VERSION 5.7 ;
  NOWIREEXTENSIONATPIN ON ;
  DIVIDERCHAR "/" ;
  BUSBITCHARS "[]" ;
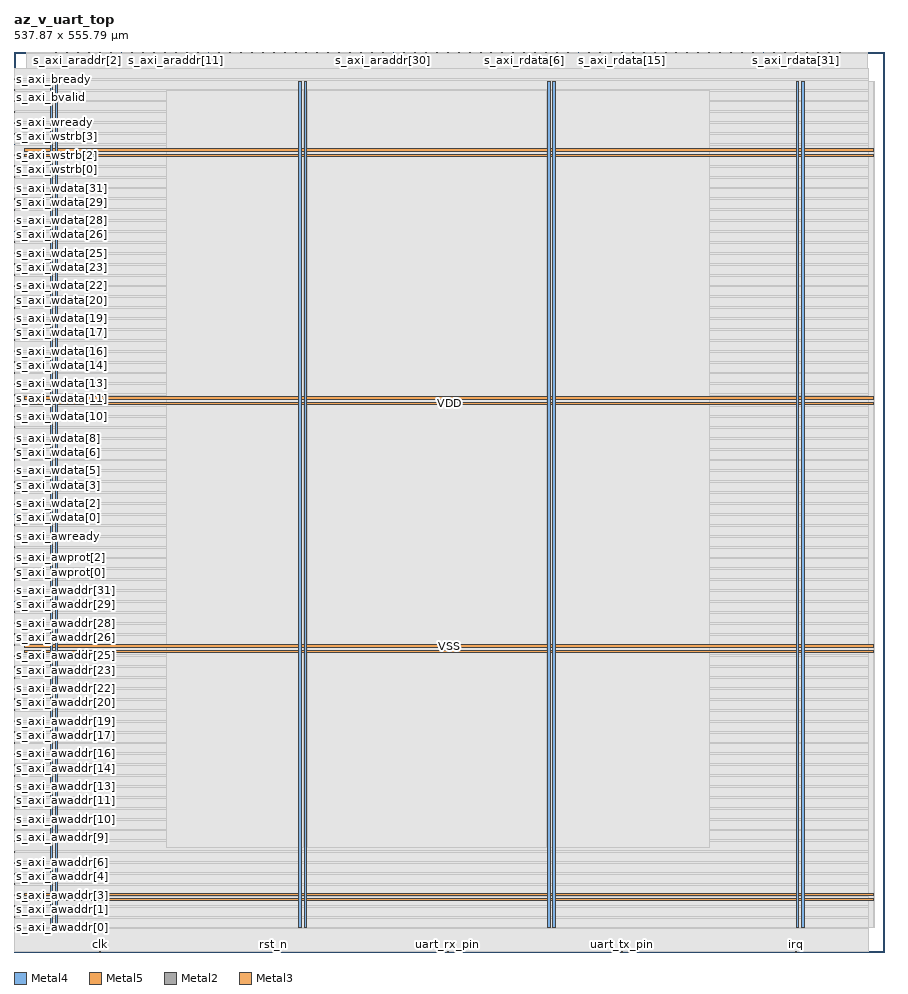
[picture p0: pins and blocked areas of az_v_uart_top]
MACRO az_v_uart_top
  CLASS BLOCK ;
  FOREIGN az_v_uart_top ;
  ORIGIN 0.000 0.000 ;
  SIZE 537.870 BY 555.790 ;
  PIN VDD
    DIRECTION INOUT ;
    USE POWER ;
    PORT
      LAYER Metal4 ;
        RECT 22.240 15.380 23.840 537.340 ;
    END
    PORT
      LAYER Metal4 ;
        RECT 175.840 15.380 177.440 537.340 ;
    END
    PORT
      LAYER Metal4 ;
        RECT 329.440 15.380 331.040 537.340 ;
    END
    PORT
      LAYER Metal4 ;
        RECT 483.040 15.380 484.640 537.340 ;
    END
    PORT
      LAYER Metal5 ;
        RECT 6.720 31.530 530.880 33.130 ;
    END
    PORT
      LAYER Metal5 ;
        RECT 6.720 184.710 530.880 186.310 ;
    END
    PORT
      LAYER Metal5 ;
        RECT 6.720 337.890 530.880 339.490 ;
    END
    PORT
      LAYER Metal5 ;
        RECT 6.720 491.070 530.880 492.670 ;
    END
  END VDD
  PIN VSS
    DIRECTION INOUT ;
    USE GROUND ;
    PORT
      LAYER Metal4 ;
        RECT 25.540 15.380 27.140 537.340 ;
    END
    PORT
      LAYER Metal4 ;
        RECT 179.140 15.380 180.740 537.340 ;
    END
    PORT
      LAYER Metal4 ;
        RECT 332.740 15.380 334.340 537.340 ;
    END
    PORT
      LAYER Metal4 ;
        RECT 486.340 15.380 487.940 537.340 ;
    END
    PORT
      LAYER Metal5 ;
        RECT 6.720 34.830 530.880 36.430 ;
    END
    PORT
      LAYER Metal5 ;
        RECT 6.720 188.010 530.880 189.610 ;
    END
    PORT
      LAYER Metal5 ;
        RECT 6.720 341.190 530.880 342.790 ;
    END
    PORT
      LAYER Metal5 ;
        RECT 6.720 494.370 530.880 495.970 ;
    END
  END VSS
  PIN clk
    DIRECTION INPUT ;
    USE SIGNAL ;
    ANTENNAGATEAREA 4.738000 ;
    PORT
      LAYER Metal2 ;
        RECT 52.640 0.000 53.200 0.560 ;
    END
  END clk
  PIN irq
    DIRECTION OUTPUT ;
    USE SIGNAL ;
    ANTENNADIFFAREA 0.897600 ;
    PORT
      LAYER Metal2 ;
        RECT 482.720 0.000 483.280 0.560 ;
    END
  END irq
  PIN rst_n
    DIRECTION INPUT ;
    USE SIGNAL ;
    ANTENNAGATEAREA 0.396000 ;
    PORT
      LAYER Metal2 ;
        RECT 160.160 0.000 160.720 0.560 ;
    END
  END rst_n
  PIN s_axi_araddr[0]
    DIRECTION INPUT ;
    USE SIGNAL ;
    ANTENNAGATEAREA 0.396000 ;
    PORT
      LAYER Metal2 ;
        RECT 25.760 555.230 26.320 555.790 ;
    END
  END s_axi_araddr[0]
  PIN s_axi_araddr[10]
    DIRECTION INPUT ;
    USE SIGNAL ;
    PORT
      LAYER Metal2 ;
        RECT 92.960 555.230 93.520 555.790 ;
    END
  END s_axi_araddr[10]
  PIN s_axi_araddr[11]
    DIRECTION INPUT ;
    USE SIGNAL ;
    PORT
      LAYER Metal2 ;
        RECT 99.680 555.230 100.240 555.790 ;
    END
  END s_axi_araddr[11]
  PIN s_axi_araddr[12]
    DIRECTION INPUT ;
    USE SIGNAL ;
    PORT
      LAYER Metal2 ;
        RECT 106.400 555.230 106.960 555.790 ;
    END
  END s_axi_araddr[12]
  PIN s_axi_araddr[13]
    DIRECTION INPUT ;
    USE SIGNAL ;
    PORT
      LAYER Metal2 ;
        RECT 113.120 555.230 113.680 555.790 ;
    END
  END s_axi_araddr[13]
  PIN s_axi_araddr[14]
    DIRECTION INPUT ;
    USE SIGNAL ;
    PORT
      LAYER Metal2 ;
        RECT 119.840 555.230 120.400 555.790 ;
    END
  END s_axi_araddr[14]
  PIN s_axi_araddr[15]
    DIRECTION INPUT ;
    USE SIGNAL ;
    PORT
      LAYER Metal2 ;
        RECT 126.560 555.230 127.120 555.790 ;
    END
  END s_axi_araddr[15]
  PIN s_axi_araddr[16]
    DIRECTION INPUT ;
    USE SIGNAL ;
    PORT
      LAYER Metal2 ;
        RECT 133.280 555.230 133.840 555.790 ;
    END
  END s_axi_araddr[16]
  PIN s_axi_araddr[17]
    DIRECTION INPUT ;
    USE SIGNAL ;
    PORT
      LAYER Metal2 ;
        RECT 140.000 555.230 140.560 555.790 ;
    END
  END s_axi_araddr[17]
  PIN s_axi_araddr[18]
    DIRECTION INPUT ;
    USE SIGNAL ;
    PORT
      LAYER Metal2 ;
        RECT 146.720 555.230 147.280 555.790 ;
    END
  END s_axi_araddr[18]
  PIN s_axi_araddr[19]
    DIRECTION INPUT ;
    USE SIGNAL ;
    PORT
      LAYER Metal2 ;
        RECT 153.440 555.230 154.000 555.790 ;
    END
  END s_axi_araddr[19]
  PIN s_axi_araddr[1]
    DIRECTION INPUT ;
    USE SIGNAL ;
    ANTENNAGATEAREA 0.396000 ;
    PORT
      LAYER Metal2 ;
        RECT 32.480 555.230 33.040 555.790 ;
    END
  END s_axi_araddr[1]
  PIN s_axi_araddr[20]
    DIRECTION INPUT ;
    USE SIGNAL ;
    PORT
      LAYER Metal2 ;
        RECT 160.160 555.230 160.720 555.790 ;
    END
  END s_axi_araddr[20]
  PIN s_axi_araddr[21]
    DIRECTION INPUT ;
    USE SIGNAL ;
    PORT
      LAYER Metal2 ;
        RECT 166.880 555.230 167.440 555.790 ;
    END
  END s_axi_araddr[21]
  PIN s_axi_araddr[22]
    DIRECTION INPUT ;
    USE SIGNAL ;
    PORT
      LAYER Metal2 ;
        RECT 173.600 555.230 174.160 555.790 ;
    END
  END s_axi_araddr[22]
  PIN s_axi_araddr[23]
    DIRECTION INPUT ;
    USE SIGNAL ;
    PORT
      LAYER Metal2 ;
        RECT 180.320 555.230 180.880 555.790 ;
    END
  END s_axi_araddr[23]
  PIN s_axi_araddr[24]
    DIRECTION INPUT ;
    USE SIGNAL ;
    PORT
      LAYER Metal2 ;
        RECT 187.040 555.230 187.600 555.790 ;
    END
  END s_axi_araddr[24]
  PIN s_axi_araddr[25]
    DIRECTION INPUT ;
    USE SIGNAL ;
    PORT
      LAYER Metal2 ;
        RECT 193.760 555.230 194.320 555.790 ;
    END
  END s_axi_araddr[25]
  PIN s_axi_araddr[26]
    DIRECTION INPUT ;
    USE SIGNAL ;
    PORT
      LAYER Metal2 ;
        RECT 200.480 555.230 201.040 555.790 ;
    END
  END s_axi_araddr[26]
  PIN s_axi_araddr[27]
    DIRECTION INPUT ;
    USE SIGNAL ;
    PORT
      LAYER Metal2 ;
        RECT 207.200 555.230 207.760 555.790 ;
    END
  END s_axi_araddr[27]
  PIN s_axi_araddr[28]
    DIRECTION INPUT ;
    USE SIGNAL ;
    PORT
      LAYER Metal2 ;
        RECT 213.920 555.230 214.480 555.790 ;
    END
  END s_axi_araddr[28]
  PIN s_axi_araddr[29]
    DIRECTION INPUT ;
    USE SIGNAL ;
    PORT
      LAYER Metal2 ;
        RECT 220.640 555.230 221.200 555.790 ;
    END
  END s_axi_araddr[29]
  PIN s_axi_araddr[2]
    DIRECTION INPUT ;
    USE SIGNAL ;
    ANTENNAGATEAREA 0.396000 ;
    PORT
      LAYER Metal2 ;
        RECT 39.200 555.230 39.760 555.790 ;
    END
  END s_axi_araddr[2]
  PIN s_axi_araddr[30]
    DIRECTION INPUT ;
    USE SIGNAL ;
    PORT
      LAYER Metal2 ;
        RECT 227.360 555.230 227.920 555.790 ;
    END
  END s_axi_araddr[30]
  PIN s_axi_araddr[31]
    DIRECTION INPUT ;
    USE SIGNAL ;
    PORT
      LAYER Metal2 ;
        RECT 234.080 555.230 234.640 555.790 ;
    END
  END s_axi_araddr[31]
  PIN s_axi_araddr[3]
    DIRECTION INPUT ;
    USE SIGNAL ;
    ANTENNAGATEAREA 0.396000 ;
    PORT
      LAYER Metal2 ;
        RECT 45.920 555.230 46.480 555.790 ;
    END
  END s_axi_araddr[3]
  PIN s_axi_araddr[4]
    DIRECTION INPUT ;
    USE SIGNAL ;
    ANTENNAGATEAREA 0.396000 ;
    PORT
      LAYER Metal2 ;
        RECT 52.640 555.230 53.200 555.790 ;
    END
  END s_axi_araddr[4]
  PIN s_axi_araddr[5]
    DIRECTION INPUT ;
    USE SIGNAL ;
    ANTENNAGATEAREA 0.396000 ;
    PORT
      LAYER Metal2 ;
        RECT 59.360 555.230 59.920 555.790 ;
    END
  END s_axi_araddr[5]
  PIN s_axi_araddr[6]
    DIRECTION INPUT ;
    USE SIGNAL ;
    PORT
      LAYER Metal2 ;
        RECT 66.080 555.230 66.640 555.790 ;
    END
  END s_axi_araddr[6]
  PIN s_axi_araddr[7]
    DIRECTION INPUT ;
    USE SIGNAL ;
    PORT
      LAYER Metal2 ;
        RECT 72.800 555.230 73.360 555.790 ;
    END
  END s_axi_araddr[7]
  PIN s_axi_araddr[8]
    DIRECTION INPUT ;
    USE SIGNAL ;
    PORT
      LAYER Metal2 ;
        RECT 79.520 555.230 80.080 555.790 ;
    END
  END s_axi_araddr[8]
  PIN s_axi_araddr[9]
    DIRECTION INPUT ;
    USE SIGNAL ;
    PORT
      LAYER Metal2 ;
        RECT 86.240 555.230 86.800 555.790 ;
    END
  END s_axi_araddr[9]
  PIN s_axi_arprot[0]
    DIRECTION INPUT ;
    USE SIGNAL ;
    PORT
      LAYER Metal2 ;
        RECT 240.800 555.230 241.360 555.790 ;
    END
  END s_axi_arprot[0]
  PIN s_axi_arprot[1]
    DIRECTION INPUT ;
    USE SIGNAL ;
    PORT
      LAYER Metal2 ;
        RECT 247.520 555.230 248.080 555.790 ;
    END
  END s_axi_arprot[1]
  PIN s_axi_arprot[2]
    DIRECTION INPUT ;
    USE SIGNAL ;
    PORT
      LAYER Metal2 ;
        RECT 254.240 555.230 254.800 555.790 ;
    END
  END s_axi_arprot[2]
  PIN s_axi_arready
    DIRECTION OUTPUT ;
    USE SIGNAL ;
    ANTENNADIFFAREA 0.897600 ;
    PORT
      LAYER Metal2 ;
        RECT 267.680 555.230 268.240 555.790 ;
    END
  END s_axi_arready
  PIN s_axi_arvalid
    DIRECTION INPUT ;
    USE SIGNAL ;
    ANTENNAGATEAREA 0.396000 ;
    PORT
      LAYER Metal2 ;
        RECT 260.960 555.230 261.520 555.790 ;
    END
  END s_axi_arvalid
  PIN s_axi_awaddr[0]
    DIRECTION INPUT ;
    USE SIGNAL ;
    ANTENNAGATEAREA 0.396000 ;
    PORT
      LAYER Metal3 ;
        RECT 0.000 14.560 0.560 15.120 ;
    END
  END s_axi_awaddr[0]
  PIN s_axi_awaddr[10]
    DIRECTION INPUT ;
    USE SIGNAL ;
    PORT
      LAYER Metal3 ;
        RECT 0.000 81.760 0.560 82.320 ;
    END
  END s_axi_awaddr[10]
  PIN s_axi_awaddr[11]
    DIRECTION INPUT ;
    USE SIGNAL ;
    PORT
      LAYER Metal3 ;
        RECT 0.000 88.480 0.560 89.040 ;
    END
  END s_axi_awaddr[11]
  PIN s_axi_awaddr[12]
    DIRECTION INPUT ;
    USE SIGNAL ;
    PORT
      LAYER Metal3 ;
        RECT 0.000 95.200 0.560 95.760 ;
    END
  END s_axi_awaddr[12]
  PIN s_axi_awaddr[13]
    DIRECTION INPUT ;
    USE SIGNAL ;
    PORT
      LAYER Metal3 ;
        RECT 0.000 101.920 0.560 102.480 ;
    END
  END s_axi_awaddr[13]
  PIN s_axi_awaddr[14]
    DIRECTION INPUT ;
    USE SIGNAL ;
    PORT
      LAYER Metal3 ;
        RECT 0.000 108.640 0.560 109.200 ;
    END
  END s_axi_awaddr[14]
  PIN s_axi_awaddr[15]
    DIRECTION INPUT ;
    USE SIGNAL ;
    PORT
      LAYER Metal3 ;
        RECT 0.000 115.360 0.560 115.920 ;
    END
  END s_axi_awaddr[15]
  PIN s_axi_awaddr[16]
    DIRECTION INPUT ;
    USE SIGNAL ;
    PORT
      LAYER Metal3 ;
        RECT 0.000 122.080 0.560 122.640 ;
    END
  END s_axi_awaddr[16]
  PIN s_axi_awaddr[17]
    DIRECTION INPUT ;
    USE SIGNAL ;
    PORT
      LAYER Metal3 ;
        RECT 0.000 128.800 0.560 129.360 ;
    END
  END s_axi_awaddr[17]
  PIN s_axi_awaddr[18]
    DIRECTION INPUT ;
    USE SIGNAL ;
    PORT
      LAYER Metal3 ;
        RECT 0.000 135.520 0.560 136.080 ;
    END
  END s_axi_awaddr[18]
  PIN s_axi_awaddr[19]
    DIRECTION INPUT ;
    USE SIGNAL ;
    PORT
      LAYER Metal3 ;
        RECT 0.000 142.240 0.560 142.800 ;
    END
  END s_axi_awaddr[19]
  PIN s_axi_awaddr[1]
    DIRECTION INPUT ;
    USE SIGNAL ;
    ANTENNAGATEAREA 0.396000 ;
    PORT
      LAYER Metal3 ;
        RECT 0.000 21.280 0.560 21.840 ;
    END
  END s_axi_awaddr[1]
  PIN s_axi_awaddr[20]
    DIRECTION INPUT ;
    USE SIGNAL ;
    PORT
      LAYER Metal3 ;
        RECT 0.000 148.960 0.560 149.520 ;
    END
  END s_axi_awaddr[20]
  PIN s_axi_awaddr[21]
    DIRECTION INPUT ;
    USE SIGNAL ;
    PORT
      LAYER Metal3 ;
        RECT 0.000 155.680 0.560 156.240 ;
    END
  END s_axi_awaddr[21]
  PIN s_axi_awaddr[22]
    DIRECTION INPUT ;
    USE SIGNAL ;
    PORT
      LAYER Metal3 ;
        RECT 0.000 162.400 0.560 162.960 ;
    END
  END s_axi_awaddr[22]
  PIN s_axi_awaddr[23]
    DIRECTION INPUT ;
    USE SIGNAL ;
    PORT
      LAYER Metal3 ;
        RECT 0.000 169.120 0.560 169.680 ;
    END
  END s_axi_awaddr[23]
  PIN s_axi_awaddr[24]
    DIRECTION INPUT ;
    USE SIGNAL ;
    PORT
      LAYER Metal3 ;
        RECT 0.000 175.840 0.560 176.400 ;
    END
  END s_axi_awaddr[24]
  PIN s_axi_awaddr[25]
    DIRECTION INPUT ;
    USE SIGNAL ;
    PORT
      LAYER Metal3 ;
        RECT 0.000 182.560 0.560 183.120 ;
    END
  END s_axi_awaddr[25]
  PIN s_axi_awaddr[26]
    DIRECTION INPUT ;
    USE SIGNAL ;
    PORT
      LAYER Metal3 ;
        RECT 0.000 189.280 0.560 189.840 ;
    END
  END s_axi_awaddr[26]
  PIN s_axi_awaddr[27]
    DIRECTION INPUT ;
    USE SIGNAL ;
    PORT
      LAYER Metal3 ;
        RECT 0.000 196.000 0.560 196.560 ;
    END
  END s_axi_awaddr[27]
  PIN s_axi_awaddr[28]
    DIRECTION INPUT ;
    USE SIGNAL ;
    PORT
      LAYER Metal3 ;
        RECT 0.000 202.720 0.560 203.280 ;
    END
  END s_axi_awaddr[28]
  PIN s_axi_awaddr[29]
    DIRECTION INPUT ;
    USE SIGNAL ;
    PORT
      LAYER Metal3 ;
        RECT 0.000 209.440 0.560 210.000 ;
    END
  END s_axi_awaddr[29]
  PIN s_axi_awaddr[2]
    DIRECTION INPUT ;
    USE SIGNAL ;
    ANTENNAGATEAREA 0.396000 ;
    PORT
      LAYER Metal3 ;
        RECT 0.000 28.000 0.560 28.560 ;
    END
  END s_axi_awaddr[2]
  PIN s_axi_awaddr[30]
    DIRECTION INPUT ;
    USE SIGNAL ;
    PORT
      LAYER Metal3 ;
        RECT 0.000 216.160 0.560 216.720 ;
    END
  END s_axi_awaddr[30]
  PIN s_axi_awaddr[31]
    DIRECTION INPUT ;
    USE SIGNAL ;
    PORT
      LAYER Metal3 ;
        RECT 0.000 222.880 0.560 223.440 ;
    END
  END s_axi_awaddr[31]
  PIN s_axi_awaddr[3]
    DIRECTION INPUT ;
    USE SIGNAL ;
    ANTENNAGATEAREA 0.396000 ;
    PORT
      LAYER Metal3 ;
        RECT 0.000 34.720 0.560 35.280 ;
    END
  END s_axi_awaddr[3]
  PIN s_axi_awaddr[4]
    DIRECTION INPUT ;
    USE SIGNAL ;
    ANTENNAGATEAREA 0.396000 ;
    PORT
      LAYER Metal3 ;
        RECT 0.000 41.440 0.560 42.000 ;
    END
  END s_axi_awaddr[4]
  PIN s_axi_awaddr[5]
    DIRECTION INPUT ;
    USE SIGNAL ;
    ANTENNAGATEAREA 0.396000 ;
    PORT
      LAYER Metal3 ;
        RECT 0.000 48.160 0.560 48.720 ;
    END
  END s_axi_awaddr[5]
  PIN s_axi_awaddr[6]
    DIRECTION INPUT ;
    USE SIGNAL ;
    PORT
      LAYER Metal3 ;
        RECT 0.000 54.880 0.560 55.440 ;
    END
  END s_axi_awaddr[6]
  PIN s_axi_awaddr[7]
    DIRECTION INPUT ;
    USE SIGNAL ;
    PORT
      LAYER Metal3 ;
        RECT 0.000 61.600 0.560 62.160 ;
    END
  END s_axi_awaddr[7]
  PIN s_axi_awaddr[8]
    DIRECTION INPUT ;
    USE SIGNAL ;
    PORT
      LAYER Metal3 ;
        RECT 0.000 68.320 0.560 68.880 ;
    END
  END s_axi_awaddr[8]
  PIN s_axi_awaddr[9]
    DIRECTION INPUT ;
    USE SIGNAL ;
    PORT
      LAYER Metal3 ;
        RECT 0.000 75.040 0.560 75.600 ;
    END
  END s_axi_awaddr[9]
  PIN s_axi_awprot[0]
    DIRECTION INPUT ;
    USE SIGNAL ;
    PORT
      LAYER Metal3 ;
        RECT 0.000 229.600 0.560 230.160 ;
    END
  END s_axi_awprot[0]
  PIN s_axi_awprot[1]
    DIRECTION INPUT ;
    USE SIGNAL ;
    PORT
      LAYER Metal3 ;
        RECT 0.000 236.320 0.560 236.880 ;
    END
  END s_axi_awprot[1]
  PIN s_axi_awprot[2]
    DIRECTION INPUT ;
    USE SIGNAL ;
    PORT
      LAYER Metal3 ;
        RECT 0.000 243.040 0.560 243.600 ;
    END
  END s_axi_awprot[2]
  PIN s_axi_awready
    DIRECTION OUTPUT ;
    USE SIGNAL ;
    ANTENNADIFFAREA 0.897600 ;
    PORT
      LAYER Metal3 ;
        RECT 0.000 256.480 0.560 257.040 ;
    END
  END s_axi_awready
  PIN s_axi_awvalid
    DIRECTION INPUT ;
    USE SIGNAL ;
    ANTENNAGATEAREA 0.396000 ;
    PORT
      LAYER Metal3 ;
        RECT 0.000 249.760 0.560 250.320 ;
    END
  END s_axi_awvalid
  PIN s_axi_bready
    DIRECTION INPUT ;
    USE SIGNAL ;
    ANTENNAGATEAREA 0.396000 ;
    PORT
      LAYER Metal3 ;
        RECT 0.000 538.720 0.560 539.280 ;
    END
  END s_axi_bready
  PIN s_axi_bresp[0]
    DIRECTION OUTPUT ;
    USE SIGNAL ;
    ANTENNADIFFAREA 0.360800 ;
    PORT
      LAYER Metal3 ;
        RECT 0.000 518.560 0.560 519.120 ;
    END
  END s_axi_bresp[0]
  PIN s_axi_bresp[1]
    DIRECTION OUTPUT ;
    USE SIGNAL ;
    ANTENNADIFFAREA 0.360800 ;
    PORT
      LAYER Metal3 ;
        RECT 0.000 525.280 0.560 525.840 ;
    END
  END s_axi_bresp[1]
  PIN s_axi_bvalid
    DIRECTION OUTPUT ;
    USE SIGNAL ;
    ANTENNADIFFAREA 0.897600 ;
    PORT
      LAYER Metal3 ;
        RECT 0.000 532.000 0.560 532.560 ;
    END
  END s_axi_bvalid
  PIN s_axi_rdata[0]
    DIRECTION OUTPUT ;
    USE SIGNAL ;
    ANTENNADIFFAREA 0.897600 ;
    PORT
      LAYER Metal2 ;
        RECT 274.400 555.230 274.960 555.790 ;
    END
  END s_axi_rdata[0]
  PIN s_axi_rdata[10]
    DIRECTION OUTPUT ;
    USE SIGNAL ;
    ANTENNADIFFAREA 0.897600 ;
    PORT
      LAYER Metal2 ;
        RECT 341.600 555.230 342.160 555.790 ;
    END
  END s_axi_rdata[10]
  PIN s_axi_rdata[11]
    DIRECTION OUTPUT ;
    USE SIGNAL ;
    ANTENNADIFFAREA 0.897600 ;
    PORT
      LAYER Metal2 ;
        RECT 348.320 555.230 348.880 555.790 ;
    END
  END s_axi_rdata[11]
  PIN s_axi_rdata[12]
    DIRECTION OUTPUT ;
    USE SIGNAL ;
    ANTENNADIFFAREA 0.897600 ;
    PORT
      LAYER Metal2 ;
        RECT 355.040 555.230 355.600 555.790 ;
    END
  END s_axi_rdata[12]
  PIN s_axi_rdata[13]
    DIRECTION OUTPUT ;
    USE SIGNAL ;
    ANTENNADIFFAREA 0.897600 ;
    PORT
      LAYER Metal2 ;
        RECT 361.760 555.230 362.320 555.790 ;
    END
  END s_axi_rdata[13]
  PIN s_axi_rdata[14]
    DIRECTION OUTPUT ;
    USE SIGNAL ;
    ANTENNADIFFAREA 0.897600 ;
    PORT
      LAYER Metal2 ;
        RECT 368.480 555.230 369.040 555.790 ;
    END
  END s_axi_rdata[14]
  PIN s_axi_rdata[15]
    DIRECTION OUTPUT ;
    USE SIGNAL ;
    ANTENNADIFFAREA 0.897600 ;
    PORT
      LAYER Metal2 ;
        RECT 375.200 555.230 375.760 555.790 ;
    END
  END s_axi_rdata[15]
  PIN s_axi_rdata[16]
    DIRECTION OUTPUT ;
    USE SIGNAL ;
    ANTENNADIFFAREA 0.897600 ;
    PORT
      LAYER Metal2 ;
        RECT 381.920 555.230 382.480 555.790 ;
    END
  END s_axi_rdata[16]
  PIN s_axi_rdata[17]
    DIRECTION OUTPUT ;
    USE SIGNAL ;
    ANTENNADIFFAREA 0.897600 ;
    PORT
      LAYER Metal2 ;
        RECT 388.640 555.230 389.200 555.790 ;
    END
  END s_axi_rdata[17]
  PIN s_axi_rdata[18]
    DIRECTION OUTPUT ;
    USE SIGNAL ;
    ANTENNADIFFAREA 0.897600 ;
    PORT
      LAYER Metal2 ;
        RECT 395.360 555.230 395.920 555.790 ;
    END
  END s_axi_rdata[18]
  PIN s_axi_rdata[19]
    DIRECTION OUTPUT ;
    USE SIGNAL ;
    ANTENNADIFFAREA 0.897600 ;
    PORT
      LAYER Metal2 ;
        RECT 402.080 555.230 402.640 555.790 ;
    END
  END s_axi_rdata[19]
  PIN s_axi_rdata[1]
    DIRECTION OUTPUT ;
    USE SIGNAL ;
    ANTENNADIFFAREA 0.897600 ;
    PORT
      LAYER Metal2 ;
        RECT 281.120 555.230 281.680 555.790 ;
    END
  END s_axi_rdata[1]
  PIN s_axi_rdata[20]
    DIRECTION OUTPUT ;
    USE SIGNAL ;
    ANTENNADIFFAREA 0.897600 ;
    PORT
      LAYER Metal2 ;
        RECT 408.800 555.230 409.360 555.790 ;
    END
  END s_axi_rdata[20]
  PIN s_axi_rdata[21]
    DIRECTION OUTPUT ;
    USE SIGNAL ;
    ANTENNADIFFAREA 0.897600 ;
    PORT
      LAYER Metal2 ;
        RECT 415.520 555.230 416.080 555.790 ;
    END
  END s_axi_rdata[21]
  PIN s_axi_rdata[22]
    DIRECTION OUTPUT ;
    USE SIGNAL ;
    ANTENNADIFFAREA 0.897600 ;
    PORT
      LAYER Metal2 ;
        RECT 422.240 555.230 422.800 555.790 ;
    END
  END s_axi_rdata[22]
  PIN s_axi_rdata[23]
    DIRECTION OUTPUT ;
    USE SIGNAL ;
    ANTENNADIFFAREA 0.897600 ;
    PORT
      LAYER Metal2 ;
        RECT 428.960 555.230 429.520 555.790 ;
    END
  END s_axi_rdata[23]
  PIN s_axi_rdata[24]
    DIRECTION OUTPUT ;
    USE SIGNAL ;
    ANTENNADIFFAREA 0.897600 ;
    PORT
      LAYER Metal2 ;
        RECT 435.680 555.230 436.240 555.790 ;
    END
  END s_axi_rdata[24]
  PIN s_axi_rdata[25]
    DIRECTION OUTPUT ;
    USE SIGNAL ;
    ANTENNADIFFAREA 0.897600 ;
    PORT
      LAYER Metal2 ;
        RECT 442.400 555.230 442.960 555.790 ;
    END
  END s_axi_rdata[25]
  PIN s_axi_rdata[26]
    DIRECTION OUTPUT ;
    USE SIGNAL ;
    ANTENNADIFFAREA 0.897600 ;
    PORT
      LAYER Metal2 ;
        RECT 449.120 555.230 449.680 555.790 ;
    END
  END s_axi_rdata[26]
  PIN s_axi_rdata[27]
    DIRECTION OUTPUT ;
    USE SIGNAL ;
    ANTENNADIFFAREA 0.897600 ;
    PORT
      LAYER Metal2 ;
        RECT 455.840 555.230 456.400 555.790 ;
    END
  END s_axi_rdata[27]
  PIN s_axi_rdata[28]
    DIRECTION OUTPUT ;
    USE SIGNAL ;
    ANTENNADIFFAREA 0.897600 ;
    PORT
      LAYER Metal2 ;
        RECT 462.560 555.230 463.120 555.790 ;
    END
  END s_axi_rdata[28]
  PIN s_axi_rdata[29]
    DIRECTION OUTPUT ;
    USE SIGNAL ;
    ANTENNADIFFAREA 0.897600 ;
    PORT
      LAYER Metal2 ;
        RECT 469.280 555.230 469.840 555.790 ;
    END
  END s_axi_rdata[29]
  PIN s_axi_rdata[2]
    DIRECTION OUTPUT ;
    USE SIGNAL ;
    ANTENNADIFFAREA 0.897600 ;
    PORT
      LAYER Metal2 ;
        RECT 287.840 555.230 288.400 555.790 ;
    END
  END s_axi_rdata[2]
  PIN s_axi_rdata[30]
    DIRECTION OUTPUT ;
    USE SIGNAL ;
    ANTENNADIFFAREA 0.897600 ;
    PORT
      LAYER Metal2 ;
        RECT 476.000 555.230 476.560 555.790 ;
    END
  END s_axi_rdata[30]
  PIN s_axi_rdata[31]
    DIRECTION OUTPUT ;
    USE SIGNAL ;
    ANTENNADIFFAREA 0.897600 ;
    PORT
      LAYER Metal2 ;
        RECT 482.720 555.230 483.280 555.790 ;
    END
  END s_axi_rdata[31]
  PIN s_axi_rdata[3]
    DIRECTION OUTPUT ;
    USE SIGNAL ;
    ANTENNADIFFAREA 0.897600 ;
    PORT
      LAYER Metal2 ;
        RECT 294.560 555.230 295.120 555.790 ;
    END
  END s_axi_rdata[3]
  PIN s_axi_rdata[4]
    DIRECTION OUTPUT ;
    USE SIGNAL ;
    ANTENNADIFFAREA 0.897600 ;
    PORT
      LAYER Metal2 ;
        RECT 301.280 555.230 301.840 555.790 ;
    END
  END s_axi_rdata[4]
  PIN s_axi_rdata[5]
    DIRECTION OUTPUT ;
    USE SIGNAL ;
    ANTENNADIFFAREA 0.897600 ;
    PORT
      LAYER Metal2 ;
        RECT 308.000 555.230 308.560 555.790 ;
    END
  END s_axi_rdata[5]
  PIN s_axi_rdata[6]
    DIRECTION OUTPUT ;
    USE SIGNAL ;
    ANTENNADIFFAREA 0.897600 ;
    PORT
      LAYER Metal2 ;
        RECT 314.720 555.230 315.280 555.790 ;
    END
  END s_axi_rdata[6]
  PIN s_axi_rdata[7]
    DIRECTION OUTPUT ;
    USE SIGNAL ;
    ANTENNADIFFAREA 0.897600 ;
    PORT
      LAYER Metal2 ;
        RECT 321.440 555.230 322.000 555.790 ;
    END
  END s_axi_rdata[7]
  PIN s_axi_rdata[8]
    DIRECTION OUTPUT ;
    USE SIGNAL ;
    ANTENNADIFFAREA 0.897600 ;
    PORT
      LAYER Metal2 ;
        RECT 328.160 555.230 328.720 555.790 ;
    END
  END s_axi_rdata[8]
  PIN s_axi_rdata[9]
    DIRECTION OUTPUT ;
    USE SIGNAL ;
    ANTENNADIFFAREA 0.897600 ;
    PORT
      LAYER Metal2 ;
        RECT 334.880 555.230 335.440 555.790 ;
    END
  END s_axi_rdata[9]
  PIN s_axi_rready
    DIRECTION INPUT ;
    USE SIGNAL ;
    ANTENNAGATEAREA 0.396000 ;
    PORT
      LAYER Metal2 ;
        RECT 509.600 555.230 510.160 555.790 ;
    END
  END s_axi_rready
  PIN s_axi_rresp[0]
    DIRECTION OUTPUT ;
    USE SIGNAL ;
    ANTENNADIFFAREA 0.360800 ;
    PORT
      LAYER Metal2 ;
        RECT 489.440 555.230 490.000 555.790 ;
    END
  END s_axi_rresp[0]
  PIN s_axi_rresp[1]
    DIRECTION OUTPUT ;
    USE SIGNAL ;
    ANTENNADIFFAREA 0.360800 ;
    PORT
      LAYER Metal2 ;
        RECT 496.160 555.230 496.720 555.790 ;
    END
  END s_axi_rresp[1]
  PIN s_axi_rvalid
    DIRECTION OUTPUT ;
    USE SIGNAL ;
    ANTENNADIFFAREA 0.897600 ;
    PORT
      LAYER Metal2 ;
        RECT 502.880 555.230 503.440 555.790 ;
    END
  END s_axi_rvalid
  PIN s_axi_wdata[0]
    DIRECTION INPUT ;
    USE SIGNAL ;
    ANTENNAGATEAREA 0.396000 ;
    PORT
      LAYER Metal3 ;
        RECT 0.000 263.200 0.560 263.760 ;
    END
  END s_axi_wdata[0]
  PIN s_axi_wdata[10]
    DIRECTION INPUT ;
    USE SIGNAL ;
    ANTENNAGATEAREA 0.396000 ;
    PORT
      LAYER Metal3 ;
        RECT 0.000 330.400 0.560 330.960 ;
    END
  END s_axi_wdata[10]
  PIN s_axi_wdata[11]
    DIRECTION INPUT ;
    USE SIGNAL ;
    ANTENNAGATEAREA 0.396000 ;
    PORT
      LAYER Metal3 ;
        RECT 0.000 337.120 0.560 337.680 ;
    END
  END s_axi_wdata[11]
  PIN s_axi_wdata[12]
    DIRECTION INPUT ;
    USE SIGNAL ;
    ANTENNAGATEAREA 0.396000 ;
    PORT
      LAYER Metal3 ;
        RECT 0.000 343.840 0.560 344.400 ;
    END
  END s_axi_wdata[12]
  PIN s_axi_wdata[13]
    DIRECTION INPUT ;
    USE SIGNAL ;
    ANTENNAGATEAREA 0.396000 ;
    PORT
      LAYER Metal3 ;
        RECT 0.000 350.560 0.560 351.120 ;
    END
  END s_axi_wdata[13]
  PIN s_axi_wdata[14]
    DIRECTION INPUT ;
    USE SIGNAL ;
    ANTENNAGATEAREA 0.396000 ;
    PORT
      LAYER Metal3 ;
        RECT 0.000 357.280 0.560 357.840 ;
    END
  END s_axi_wdata[14]
  PIN s_axi_wdata[15]
    DIRECTION INPUT ;
    USE SIGNAL ;
    ANTENNAGATEAREA 0.396000 ;
    PORT
      LAYER Metal3 ;
        RECT 0.000 364.000 0.560 364.560 ;
    END
  END s_axi_wdata[15]
  PIN s_axi_wdata[16]
    DIRECTION INPUT ;
    USE SIGNAL ;
    ANTENNAGATEAREA 0.396000 ;
    PORT
      LAYER Metal3 ;
        RECT 0.000 370.720 0.560 371.280 ;
    END
  END s_axi_wdata[16]
  PIN s_axi_wdata[17]
    DIRECTION INPUT ;
    USE SIGNAL ;
    ANTENNAGATEAREA 0.396000 ;
    PORT
      LAYER Metal3 ;
        RECT 0.000 377.440 0.560 378.000 ;
    END
  END s_axi_wdata[17]
  PIN s_axi_wdata[18]
    DIRECTION INPUT ;
    USE SIGNAL ;
    ANTENNAGATEAREA 0.396000 ;
    PORT
      LAYER Metal3 ;
        RECT 0.000 384.160 0.560 384.720 ;
    END
  END s_axi_wdata[18]
  PIN s_axi_wdata[19]
    DIRECTION INPUT ;
    USE SIGNAL ;
    ANTENNAGATEAREA 0.396000 ;
    PORT
      LAYER Metal3 ;
        RECT 0.000 390.880 0.560 391.440 ;
    END
  END s_axi_wdata[19]
  PIN s_axi_wdata[1]
    DIRECTION INPUT ;
    USE SIGNAL ;
    ANTENNAGATEAREA 0.396000 ;
    PORT
      LAYER Metal3 ;
        RECT 0.000 269.920 0.560 270.480 ;
    END
  END s_axi_wdata[1]
  PIN s_axi_wdata[20]
    DIRECTION INPUT ;
    USE SIGNAL ;
    ANTENNAGATEAREA 0.396000 ;
    PORT
      LAYER Metal3 ;
        RECT 0.000 397.600 0.560 398.160 ;
    END
  END s_axi_wdata[20]
  PIN s_axi_wdata[21]
    DIRECTION INPUT ;
    USE SIGNAL ;
    ANTENNAGATEAREA 0.396000 ;
    PORT
      LAYER Metal3 ;
        RECT 0.000 404.320 0.560 404.880 ;
    END
  END s_axi_wdata[21]
  PIN s_axi_wdata[22]
    DIRECTION INPUT ;
    USE SIGNAL ;
    ANTENNAGATEAREA 0.396000 ;
    PORT
      LAYER Metal3 ;
        RECT 0.000 411.040 0.560 411.600 ;
    END
  END s_axi_wdata[22]
  PIN s_axi_wdata[23]
    DIRECTION INPUT ;
    USE SIGNAL ;
    ANTENNAGATEAREA 0.396000 ;
    PORT
      LAYER Metal3 ;
        RECT 0.000 417.760 0.560 418.320 ;
    END
  END s_axi_wdata[23]
  PIN s_axi_wdata[24]
    DIRECTION INPUT ;
    USE SIGNAL ;
    ANTENNAGATEAREA 0.396000 ;
    PORT
      LAYER Metal3 ;
        RECT 0.000 424.480 0.560 425.040 ;
    END
  END s_axi_wdata[24]
  PIN s_axi_wdata[25]
    DIRECTION INPUT ;
    USE SIGNAL ;
    ANTENNAGATEAREA 0.396000 ;
    PORT
      LAYER Metal3 ;
        RECT 0.000 431.200 0.560 431.760 ;
    END
  END s_axi_wdata[25]
  PIN s_axi_wdata[26]
    DIRECTION INPUT ;
    USE SIGNAL ;
    ANTENNAGATEAREA 0.396000 ;
    PORT
      LAYER Metal3 ;
        RECT 0.000 437.920 0.560 438.480 ;
    END
  END s_axi_wdata[26]
  PIN s_axi_wdata[27]
    DIRECTION INPUT ;
    USE SIGNAL ;
    ANTENNAGATEAREA 0.396000 ;
    PORT
      LAYER Metal3 ;
        RECT 0.000 444.640 0.560 445.200 ;
    END
  END s_axi_wdata[27]
  PIN s_axi_wdata[28]
    DIRECTION INPUT ;
    USE SIGNAL ;
    ANTENNAGATEAREA 0.396000 ;
    PORT
      LAYER Metal3 ;
        RECT 0.000 451.360 0.560 451.920 ;
    END
  END s_axi_wdata[28]
  PIN s_axi_wdata[29]
    DIRECTION INPUT ;
    USE SIGNAL ;
    ANTENNAGATEAREA 0.396000 ;
    PORT
      LAYER Metal3 ;
        RECT 0.000 458.080 0.560 458.640 ;
    END
  END s_axi_wdata[29]
  PIN s_axi_wdata[2]
    DIRECTION INPUT ;
    USE SIGNAL ;
    ANTENNAGATEAREA 0.396000 ;
    PORT
      LAYER Metal3 ;
        RECT 0.000 276.640 0.560 277.200 ;
    END
  END s_axi_wdata[2]
  PIN s_axi_wdata[30]
    DIRECTION INPUT ;
    USE SIGNAL ;
    ANTENNAGATEAREA 0.396000 ;
    PORT
      LAYER Metal3 ;
        RECT 0.000 464.800 0.560 465.360 ;
    END
  END s_axi_wdata[30]
  PIN s_axi_wdata[31]
    DIRECTION INPUT ;
    USE SIGNAL ;
    ANTENNAGATEAREA 0.396000 ;
    PORT
      LAYER Metal3 ;
        RECT 0.000 471.520 0.560 472.080 ;
    END
  END s_axi_wdata[31]
  PIN s_axi_wdata[3]
    DIRECTION INPUT ;
    USE SIGNAL ;
    ANTENNAGATEAREA 0.396000 ;
    PORT
      LAYER Metal3 ;
        RECT 0.000 283.360 0.560 283.920 ;
    END
  END s_axi_wdata[3]
  PIN s_axi_wdata[4]
    DIRECTION INPUT ;
    USE SIGNAL ;
    ANTENNAGATEAREA 0.396000 ;
    PORT
      LAYER Metal3 ;
        RECT 0.000 290.080 0.560 290.640 ;
    END
  END s_axi_wdata[4]
  PIN s_axi_wdata[5]
    DIRECTION INPUT ;
    USE SIGNAL ;
    ANTENNAGATEAREA 0.396000 ;
    PORT
      LAYER Metal3 ;
        RECT 0.000 296.800 0.560 297.360 ;
    END
  END s_axi_wdata[5]
  PIN s_axi_wdata[6]
    DIRECTION INPUT ;
    USE SIGNAL ;
    ANTENNAGATEAREA 0.396000 ;
    PORT
      LAYER Metal3 ;
        RECT 0.000 303.520 0.560 304.080 ;
    END
  END s_axi_wdata[6]
  PIN s_axi_wdata[7]
    DIRECTION INPUT ;
    USE SIGNAL ;
    ANTENNAGATEAREA 0.396000 ;
    PORT
      LAYER Metal3 ;
        RECT 0.000 310.240 0.560 310.800 ;
    END
  END s_axi_wdata[7]
  PIN s_axi_wdata[8]
    DIRECTION INPUT ;
    USE SIGNAL ;
    ANTENNAGATEAREA 0.396000 ;
    PORT
      LAYER Metal3 ;
        RECT 0.000 316.960 0.560 317.520 ;
    END
  END s_axi_wdata[8]
  PIN s_axi_wdata[9]
    DIRECTION INPUT ;
    USE SIGNAL ;
    ANTENNAGATEAREA 0.396000 ;
    PORT
      LAYER Metal3 ;
        RECT 0.000 323.680 0.560 324.240 ;
    END
  END s_axi_wdata[9]
  PIN s_axi_wready
    DIRECTION OUTPUT ;
    USE SIGNAL ;
    ANTENNADIFFAREA 0.897600 ;
    PORT
      LAYER Metal3 ;
        RECT 0.000 511.840 0.560 512.400 ;
    END
  END s_axi_wready
  PIN s_axi_wstrb[0]
    DIRECTION INPUT ;
    USE SIGNAL ;
    PORT
      LAYER Metal3 ;
        RECT 0.000 478.240 0.560 478.800 ;
    END
  END s_axi_wstrb[0]
  PIN s_axi_wstrb[1]
    DIRECTION INPUT ;
    USE SIGNAL ;
    PORT
      LAYER Metal3 ;
        RECT 0.000 484.960 0.560 485.520 ;
    END
  END s_axi_wstrb[1]
  PIN s_axi_wstrb[2]
    DIRECTION INPUT ;
    USE SIGNAL ;
    PORT
      LAYER Metal3 ;
        RECT 0.000 491.680 0.560 492.240 ;
    END
  END s_axi_wstrb[2]
  PIN s_axi_wstrb[3]
    DIRECTION INPUT ;
    USE SIGNAL ;
    PORT
      LAYER Metal3 ;
        RECT 0.000 498.400 0.560 498.960 ;
    END
  END s_axi_wstrb[3]
  PIN s_axi_wvalid
    DIRECTION INPUT ;
    USE SIGNAL ;
    ANTENNAGATEAREA 0.396000 ;
    PORT
      LAYER Metal3 ;
        RECT 0.000 505.120 0.560 505.680 ;
    END
  END s_axi_wvalid
  PIN uart_rx_pin
    DIRECTION INPUT ;
    USE SIGNAL ;
    ANTENNAGATEAREA 0.396000 ;
    PORT
      LAYER Metal2 ;
        RECT 267.680 0.000 268.240 0.560 ;
    END
  END uart_rx_pin
  PIN uart_tx_pin
    DIRECTION OUTPUT ;
    USE SIGNAL ;
    ANTENNADIFFAREA 0.897600 ;
    PORT
      LAYER Metal2 ;
        RECT 375.200 0.000 375.760 0.560 ;
    END
  END uart_tx_pin
  OBS
      LAYER Nwell ;
        RECT 6.290 15.250 531.310 537.470 ;
      LAYER Metal1 ;
        RECT 6.720 15.380 530.880 537.340 ;
      LAYER Metal2 ;
        RECT 7.980 554.930 25.460 555.650 ;
        RECT 26.620 554.930 32.180 555.650 ;
        RECT 33.340 554.930 38.900 555.650 ;
        RECT 40.060 554.930 45.620 555.650 ;
        RECT 46.780 554.930 52.340 555.650 ;
        RECT 53.500 554.930 59.060 555.650 ;
        RECT 60.220 554.930 65.780 555.650 ;
        RECT 66.940 554.930 72.500 555.650 ;
        RECT 73.660 554.930 79.220 555.650 ;
        RECT 80.380 554.930 85.940 555.650 ;
        RECT 87.100 554.930 92.660 555.650 ;
        RECT 93.820 554.930 99.380 555.650 ;
        RECT 100.540 554.930 106.100 555.650 ;
        RECT 107.260 554.930 112.820 555.650 ;
        RECT 113.980 554.930 119.540 555.650 ;
        RECT 120.700 554.930 126.260 555.650 ;
        RECT 127.420 554.930 132.980 555.650 ;
        RECT 134.140 554.930 139.700 555.650 ;
        RECT 140.860 554.930 146.420 555.650 ;
        RECT 147.580 554.930 153.140 555.650 ;
        RECT 154.300 554.930 159.860 555.650 ;
        RECT 161.020 554.930 166.580 555.650 ;
        RECT 167.740 554.930 173.300 555.650 ;
        RECT 174.460 554.930 180.020 555.650 ;
        RECT 181.180 554.930 186.740 555.650 ;
        RECT 187.900 554.930 193.460 555.650 ;
        RECT 194.620 554.930 200.180 555.650 ;
        RECT 201.340 554.930 206.900 555.650 ;
        RECT 208.060 554.930 213.620 555.650 ;
        RECT 214.780 554.930 220.340 555.650 ;
        RECT 221.500 554.930 227.060 555.650 ;
        RECT 228.220 554.930 233.780 555.650 ;
        RECT 234.940 554.930 240.500 555.650 ;
        RECT 241.660 554.930 247.220 555.650 ;
        RECT 248.380 554.930 253.940 555.650 ;
        RECT 255.100 554.930 260.660 555.650 ;
        RECT 261.820 554.930 267.380 555.650 ;
        RECT 268.540 554.930 274.100 555.650 ;
        RECT 275.260 554.930 280.820 555.650 ;
        RECT 281.980 554.930 287.540 555.650 ;
        RECT 288.700 554.930 294.260 555.650 ;
        RECT 295.420 554.930 300.980 555.650 ;
        RECT 302.140 554.930 307.700 555.650 ;
        RECT 308.860 554.930 314.420 555.650 ;
        RECT 315.580 554.930 321.140 555.650 ;
        RECT 322.300 554.930 327.860 555.650 ;
        RECT 329.020 554.930 334.580 555.650 ;
        RECT 335.740 554.930 341.300 555.650 ;
        RECT 342.460 554.930 348.020 555.650 ;
        RECT 349.180 554.930 354.740 555.650 ;
        RECT 355.900 554.930 361.460 555.650 ;
        RECT 362.620 554.930 368.180 555.650 ;
        RECT 369.340 554.930 374.900 555.650 ;
        RECT 376.060 554.930 381.620 555.650 ;
        RECT 382.780 554.930 388.340 555.650 ;
        RECT 389.500 554.930 395.060 555.650 ;
        RECT 396.220 554.930 401.780 555.650 ;
        RECT 402.940 554.930 408.500 555.650 ;
        RECT 409.660 554.930 415.220 555.650 ;
        RECT 416.380 554.930 421.940 555.650 ;
        RECT 423.100 554.930 428.660 555.650 ;
        RECT 429.820 554.930 435.380 555.650 ;
        RECT 436.540 554.930 442.100 555.650 ;
        RECT 443.260 554.930 448.820 555.650 ;
        RECT 449.980 554.930 455.540 555.650 ;
        RECT 456.700 554.930 462.260 555.650 ;
        RECT 463.420 554.930 468.980 555.650 ;
        RECT 470.140 554.930 475.700 555.650 ;
        RECT 476.860 554.930 482.420 555.650 ;
        RECT 483.580 554.930 489.140 555.650 ;
        RECT 490.300 554.930 495.860 555.650 ;
        RECT 497.020 554.930 502.580 555.650 ;
        RECT 503.740 554.930 509.300 555.650 ;
        RECT 510.460 554.930 527.380 555.650 ;
        RECT 7.980 0.860 527.380 554.930 ;
        RECT 7.980 0.090 52.340 0.860 ;
        RECT 53.500 0.090 159.860 0.860 ;
        RECT 161.020 0.090 267.380 0.860 ;
        RECT 268.540 0.090 374.900 0.860 ;
        RECT 376.060 0.090 482.420 0.860 ;
        RECT 483.580 0.090 527.380 0.860 ;
      LAYER Metal3 ;
        RECT 0.560 539.580 527.430 545.860 ;
        RECT 0.860 538.420 527.430 539.580 ;
        RECT 0.560 532.860 527.430 538.420 ;
        RECT 0.860 531.700 527.430 532.860 ;
        RECT 0.560 526.140 527.430 531.700 ;
        RECT 0.860 524.980 527.430 526.140 ;
        RECT 0.560 519.420 527.430 524.980 ;
        RECT 0.860 518.260 527.430 519.420 ;
        RECT 0.560 512.700 527.430 518.260 ;
        RECT 0.860 511.540 527.430 512.700 ;
        RECT 0.560 505.980 527.430 511.540 ;
        RECT 0.860 504.820 527.430 505.980 ;
        RECT 0.560 499.260 527.430 504.820 ;
        RECT 0.860 498.100 527.430 499.260 ;
        RECT 0.560 492.540 527.430 498.100 ;
        RECT 0.860 491.380 527.430 492.540 ;
        RECT 0.560 485.820 527.430 491.380 ;
        RECT 0.860 484.660 527.430 485.820 ;
        RECT 0.560 479.100 527.430 484.660 ;
        RECT 0.860 477.940 527.430 479.100 ;
        RECT 0.560 472.380 527.430 477.940 ;
        RECT 0.860 471.220 527.430 472.380 ;
        RECT 0.560 465.660 527.430 471.220 ;
        RECT 0.860 464.500 527.430 465.660 ;
        RECT 0.560 458.940 527.430 464.500 ;
        RECT 0.860 457.780 527.430 458.940 ;
        RECT 0.560 452.220 527.430 457.780 ;
        RECT 0.860 451.060 527.430 452.220 ;
        RECT 0.560 445.500 527.430 451.060 ;
        RECT 0.860 444.340 527.430 445.500 ;
        RECT 0.560 438.780 527.430 444.340 ;
        RECT 0.860 437.620 527.430 438.780 ;
        RECT 0.560 432.060 527.430 437.620 ;
        RECT 0.860 430.900 527.430 432.060 ;
        RECT 0.560 425.340 527.430 430.900 ;
        RECT 0.860 424.180 527.430 425.340 ;
        RECT 0.560 418.620 527.430 424.180 ;
        RECT 0.860 417.460 527.430 418.620 ;
        RECT 0.560 411.900 527.430 417.460 ;
        RECT 0.860 410.740 527.430 411.900 ;
        RECT 0.560 405.180 527.430 410.740 ;
        RECT 0.860 404.020 527.430 405.180 ;
        RECT 0.560 398.460 527.430 404.020 ;
        RECT 0.860 397.300 527.430 398.460 ;
        RECT 0.560 391.740 527.430 397.300 ;
        RECT 0.860 390.580 527.430 391.740 ;
        RECT 0.560 385.020 527.430 390.580 ;
        RECT 0.860 383.860 527.430 385.020 ;
        RECT 0.560 378.300 527.430 383.860 ;
        RECT 0.860 377.140 527.430 378.300 ;
        RECT 0.560 371.580 527.430 377.140 ;
        RECT 0.860 370.420 527.430 371.580 ;
        RECT 0.560 364.860 527.430 370.420 ;
        RECT 0.860 363.700 527.430 364.860 ;
        RECT 0.560 358.140 527.430 363.700 ;
        RECT 0.860 356.980 527.430 358.140 ;
        RECT 0.560 351.420 527.430 356.980 ;
        RECT 0.860 350.260 527.430 351.420 ;
        RECT 0.560 344.700 527.430 350.260 ;
        RECT 0.860 343.540 527.430 344.700 ;
        RECT 0.560 337.980 527.430 343.540 ;
        RECT 0.860 336.820 527.430 337.980 ;
        RECT 0.560 331.260 527.430 336.820 ;
        RECT 0.860 330.100 527.430 331.260 ;
        RECT 0.560 324.540 527.430 330.100 ;
        RECT 0.860 323.380 527.430 324.540 ;
        RECT 0.560 317.820 527.430 323.380 ;
        RECT 0.860 316.660 527.430 317.820 ;
        RECT 0.560 311.100 527.430 316.660 ;
        RECT 0.860 309.940 527.430 311.100 ;
        RECT 0.560 304.380 527.430 309.940 ;
        RECT 0.860 303.220 527.430 304.380 ;
        RECT 0.560 297.660 527.430 303.220 ;
        RECT 0.860 296.500 527.430 297.660 ;
        RECT 0.560 290.940 527.430 296.500 ;
        RECT 0.860 289.780 527.430 290.940 ;
        RECT 0.560 284.220 527.430 289.780 ;
        RECT 0.860 283.060 527.430 284.220 ;
        RECT 0.560 277.500 527.430 283.060 ;
        RECT 0.860 276.340 527.430 277.500 ;
        RECT 0.560 270.780 527.430 276.340 ;
        RECT 0.860 269.620 527.430 270.780 ;
        RECT 0.560 264.060 527.430 269.620 ;
        RECT 0.860 262.900 527.430 264.060 ;
        RECT 0.560 257.340 527.430 262.900 ;
        RECT 0.860 256.180 527.430 257.340 ;
        RECT 0.560 250.620 527.430 256.180 ;
        RECT 0.860 249.460 527.430 250.620 ;
        RECT 0.560 243.900 527.430 249.460 ;
        RECT 0.860 242.740 527.430 243.900 ;
        RECT 0.560 237.180 527.430 242.740 ;
        RECT 0.860 236.020 527.430 237.180 ;
        RECT 0.560 230.460 527.430 236.020 ;
        RECT 0.860 229.300 527.430 230.460 ;
        RECT 0.560 223.740 527.430 229.300 ;
        RECT 0.860 222.580 527.430 223.740 ;
        RECT 0.560 217.020 527.430 222.580 ;
        RECT 0.860 215.860 527.430 217.020 ;
        RECT 0.560 210.300 527.430 215.860 ;
        RECT 0.860 209.140 527.430 210.300 ;
        RECT 0.560 203.580 527.430 209.140 ;
        RECT 0.860 202.420 527.430 203.580 ;
        RECT 0.560 196.860 527.430 202.420 ;
        RECT 0.860 195.700 527.430 196.860 ;
        RECT 0.560 190.140 527.430 195.700 ;
        RECT 0.860 188.980 527.430 190.140 ;
        RECT 0.560 183.420 527.430 188.980 ;
        RECT 0.860 182.260 527.430 183.420 ;
        RECT 0.560 176.700 527.430 182.260 ;
        RECT 0.860 175.540 527.430 176.700 ;
        RECT 0.560 169.980 527.430 175.540 ;
        RECT 0.860 168.820 527.430 169.980 ;
        RECT 0.560 163.260 527.430 168.820 ;
        RECT 0.860 162.100 527.430 163.260 ;
        RECT 0.560 156.540 527.430 162.100 ;
        RECT 0.860 155.380 527.430 156.540 ;
        RECT 0.560 149.820 527.430 155.380 ;
        RECT 0.860 148.660 527.430 149.820 ;
        RECT 0.560 143.100 527.430 148.660 ;
        RECT 0.860 141.940 527.430 143.100 ;
        RECT 0.560 136.380 527.430 141.940 ;
        RECT 0.860 135.220 527.430 136.380 ;
        RECT 0.560 129.660 527.430 135.220 ;
        RECT 0.860 128.500 527.430 129.660 ;
        RECT 0.560 122.940 527.430 128.500 ;
        RECT 0.860 121.780 527.430 122.940 ;
        RECT 0.560 116.220 527.430 121.780 ;
        RECT 0.860 115.060 527.430 116.220 ;
        RECT 0.560 109.500 527.430 115.060 ;
        RECT 0.860 108.340 527.430 109.500 ;
        RECT 0.560 102.780 527.430 108.340 ;
        RECT 0.860 101.620 527.430 102.780 ;
        RECT 0.560 96.060 527.430 101.620 ;
        RECT 0.860 94.900 527.430 96.060 ;
        RECT 0.560 89.340 527.430 94.900 ;
        RECT 0.860 88.180 527.430 89.340 ;
        RECT 0.560 82.620 527.430 88.180 ;
        RECT 0.860 81.460 527.430 82.620 ;
        RECT 0.560 75.900 527.430 81.460 ;
        RECT 0.860 74.740 527.430 75.900 ;
        RECT 0.560 69.180 527.430 74.740 ;
        RECT 0.860 68.020 527.430 69.180 ;
        RECT 0.560 62.460 527.430 68.020 ;
        RECT 0.860 61.300 527.430 62.460 ;
        RECT 0.560 55.740 527.430 61.300 ;
        RECT 0.860 54.580 527.430 55.740 ;
        RECT 0.560 49.020 527.430 54.580 ;
        RECT 0.860 47.860 527.430 49.020 ;
        RECT 0.560 42.300 527.430 47.860 ;
        RECT 0.860 41.140 527.430 42.300 ;
        RECT 0.560 35.580 527.430 41.140 ;
        RECT 0.860 34.420 527.430 35.580 ;
        RECT 0.560 28.860 527.430 34.420 ;
        RECT 0.860 27.700 527.430 28.860 ;
        RECT 0.560 22.140 527.430 27.700 ;
        RECT 0.860 20.980 527.430 22.140 ;
        RECT 0.560 15.420 527.430 20.980 ;
        RECT 0.860 14.260 527.430 15.420 ;
        RECT 0.560 0.140 527.430 14.260 ;
      LAYER Metal4 ;
        RECT 94.220 64.490 175.540 531.910 ;
        RECT 177.740 64.490 178.840 531.910 ;
        RECT 181.040 64.490 329.140 531.910 ;
        RECT 331.340 64.490 332.440 531.910 ;
        RECT 334.640 64.490 429.380 531.910 ;
  END
END az_v_uart_top
END LIBRARY

